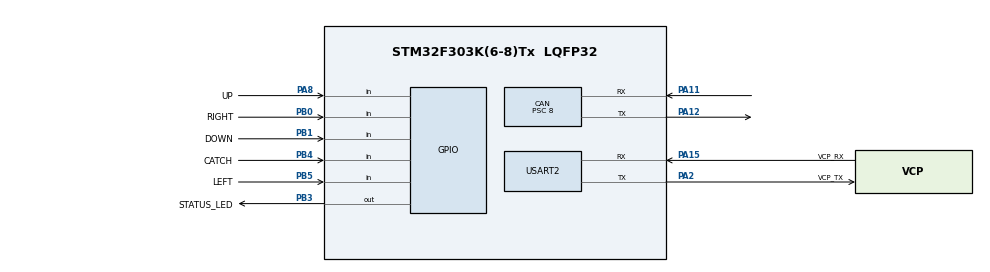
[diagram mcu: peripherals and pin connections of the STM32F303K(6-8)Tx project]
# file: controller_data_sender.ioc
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CAN.BS1=CAN_BS1_7TQ
CAN.BS2=CAN_BS2_2TQ
CAN.CalculateBaudRate=100000
CAN.CalculateTimeBit=10000
CAN.CalculateTimeQuantum=1000.0
CAN.Prescaler=8
CAN.SJW=CAN_SJW_1TQ
Mcu.Family=STM32F3
Mcu.Name=STM32F303K(6-8)Tx
Mcu.Package=LQFP32
NVIC.PriorityGroup=NVIC_PRIORITYGROUP_4
PA11.Mode=CAN_Activate
PA11.Signal=CAN_RX
PA12.Mode=CAN_Activate
PA12.Signal=CAN_TX
PA13.GPIO_Label=SWDIO
PA13.Mode=Serial_Wire
PA13.Signal=SYS_JTMS-SWDIO
PA14.GPIO_Label=SWCLK
PA14.Mode=Serial_Wire
PA14.Signal=SYS_JTCK-SWCLK
PA15.GPIO_Label=VCP_RX
PA15.Mode=Asynchronous
PA15.Signal=USART2_RX
PA2.GPIO_Label=VCP_TX
PA2.Mode=Asynchronous
PA2.Signal=USART2_TX
PA8.GPIO_Label=UP
PA8.GPIO_PuPd=GPIO_PULLUP
PA8.Signal=GPIO_Input
PB0.GPIO_Label=RIGHT
PB0.GPIO_PuPd=GPIO_PULLUP
PB0.Signal=GPIO_Input
PB1.GPIO_Label=DOWN
PB1.GPIO_PuPd=GPIO_PULLUP
PB1.Signal=GPIO_Input
PB3.GPIO_Label=STATUS_LED
PB3.Signal=GPIO_Output
PB4.GPIO_Label=CATCH
PB4.GPIO_PuPd=GPIO_PULLUP
PB4.Signal=GPIO_Input
PB5.GPIO_Label=LEFT
PB5.GPIO_PuPd=GPIO_PULLUP
PB5.Signal=GPIO_Input
PF0\ /\ OSC_IN.GPIO_Label=MCO
PF0\ /\ OSC_IN.Mode=HSE-External-Clock-Source
PF0\ /\ OSC_IN.Signal=RCC_OSC_IN
ProjectManager.HeapSize=0x200
ProjectManager.StackSize=0x400
ProjectManager.TargetToolchain=CMake
RCC.AHBFreq_Value=8000000
RCC.APB1Freq_Value=8000000
RCC.APB2Freq_Value=8000000
RCC.CortexFreq_Value=8000000
RCC.HSE_VALUE=8000000
RCC.HSI_VALUE=8000000
RCC.SYSCLKFreq_VALUE=8000000
RCC.SYSCLKSource=RCC_SYSCLKSOURCE_HSE
USART2.VirtualMode-Asynchronous=VM_ASYNC
board=NUCLEO-F303K8

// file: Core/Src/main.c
/* USER CODE BEGIN Header */
/**
  ******************************************************************************
  * @file           : main.c
  * @brief          : Main program body
  ******************************************************************************
  * @attention
  *
  * Copyright (c) 2026 STMicroelectronics.
  * All rights reserved.
  *
  * This software is licensed under terms that can be found in the LICENSE file
  * in the root directory of this software component.
  * If no LICENSE file comes with this software, it is provided AS-IS.
  *
  ******************************************************************************
  */
/* USER CODE END Header */
#include "main.h"

/* USER CODE BEGIN Includes */
#include "can.h"

/* USER CODE END Includes */

/* USER CODE BEGIN PD */
#define SEND_PERIOD_MS 10

/* USER CODE END PD */

CAN_HandleTypeDef hcan;

UART_HandleTypeDef huart2;

void SystemClock_Config(void);
static void MX_GPIO_Init(void);
static void MX_CAN_Init(void);
static void MX_USART2_UART_Init(void);

int main(void)
{

  /* MCU Configuration--------------------------------------------------------*/

  /* Reset of all peripherals, Initializes the Flash interface and the Systick. */
  HAL_Init();

  /* Configure the system clock */
  SystemClock_Config();

  /* Initialize all configured peripherals */
  MX_GPIO_Init();
  MX_CAN_Init();
  MX_USART2_UART_Init();
  /* USER CODE BEGIN 2 */
  if (HAL_CAN_Start(&hcan) != HAL_OK)
  {
    Error_Handler();
  }

  /* USER CODE END 2 */

  /* Infinite loop */
  while (1)
  {

    /* USER CODE BEGIN 3 */
    // ボタンはプルアップ入力なので押下でLOW
    can_command_data_t com = {.id = CAN_ID_CONTROLLER};
    com.data.con.raw = 0;
    com.data.con.left  = (HAL_GPIO_ReadPin(LEFT_GPIO_Port,  LEFT_Pin)  == GPIO_PIN_RESET);
    com.data.con.right = (HAL_GPIO_ReadPin(RIGHT_GPIO_Port, RIGHT_Pin) == GPIO_PIN_RESET);
    com.data.con.up    = (HAL_GPIO_ReadPin(UP_GPIO_Port,    UP_Pin)    == GPIO_PIN_RESET);
    com.data.con.down  = (HAL_GPIO_ReadPin(DOWN_GPIO_Port,  DOWN_Pin)  == GPIO_PIN_RESET);
    com.data.con.cat   = (HAL_GPIO_ReadPin(CATCH_GPIO_Port, CATCH_Pin) == GPIO_PIN_RESET);

    stm_can_send(&hcan, &com);

    // STATUS_LED: いずれかのボタンが押されている間だけ点灯
    HAL_GPIO_WritePin(STATUS_LED_GPIO_Port, STATUS_LED_Pin,
                      com.data.con.raw ? GPIO_PIN_SET : GPIO_PIN_RESET);
    HAL_Delay(SEND_PERIOD_MS);
  }
  /* USER CODE END 3 */
}

void SystemClock_Config(void)
{
  RCC_OscInitTypeDef RCC_OscInitStruct = {0};
  RCC_ClkInitTypeDef RCC_ClkInitStruct = {0};
  uint32_t sysclk_src = RCC_SYSCLKSOURCE_HSE;

  /** Initializes the RCC Oscillators according to the specified parameters
  * in the RCC_OscInitTypeDef structure.
  */
  RCC_OscInitStruct.OscillatorType = RCC_OSCILLATORTYPE_HSE;
  RCC_OscInitStruct.HSEState = RCC_HSE_BYPASS;
  RCC_OscInitStruct.HSEPredivValue = RCC_HSE_PREDIV_DIV1;
  RCC_OscInitStruct.PLL.PLLState = RCC_PLL_NONE;
  if (HAL_RCC_OscConfig(&RCC_OscInitStruct) != HAL_OK)
  {
    /* HSE(ST-LINKのMCO)が立ち上がらないときはHSIで動かす。システムクロックは同じ8MHz */
    sysclk_src = RCC_SYSCLKSOURCE_HSI;
    RCC_OscInitStruct = (RCC_OscInitTypeDef){0};
    RCC_OscInitStruct.OscillatorType = RCC_OSCILLATORTYPE_HSE|RCC_OSCILLATORTYPE_HSI;
    RCC_OscInitStruct.HSEState = RCC_HSE_OFF;
    RCC_OscInitStruct.HSIState = RCC_HSI_ON;
    RCC_OscInitStruct.HSICalibrationValue = RCC_HSICALIBRATION_DEFAULT;
    RCC_OscInitStruct.PLL.PLLState = RCC_PLL_NONE;
    if (HAL_RCC_OscConfig(&RCC_OscInitStruct) != HAL_OK)
    {
      Error_Handler();
    }
  }

  /** Initializes the CPU, AHB and APB buses clocks
  */
  RCC_ClkInitStruct.ClockType = RCC_CLOCKTYPE_HCLK|RCC_CLOCKTYPE_SYSCLK
                              |RCC_CLOCKTYPE_PCLK1|RCC_CLOCKTYPE_PCLK2;
  RCC_ClkInitStruct.SYSCLKSource = sysclk_src;
  RCC_ClkInitStruct.AHBCLKDivider = RCC_SYSCLK_DIV1;
  RCC_ClkInitStruct.APB1CLKDivider = RCC_HCLK_DIV1;
  RCC_ClkInitStruct.APB2CLKDivider = RCC_HCLK_DIV1;

  if (HAL_RCC_ClockConfig(&RCC_ClkInitStruct, FLASH_LATENCY_0) != HAL_OK)
  {
    Error_Handler();
  }
}

static void MX_CAN_Init(void)
{

  hcan.Instance = CAN;
  hcan.Init.Prescaler = 8;
  hcan.Init.Mode = CAN_MODE_NORMAL;
  hcan.Init.SyncJumpWidth = CAN_SJW_1TQ;
  hcan.Init.TimeSeg1 = CAN_BS1_7TQ;
  hcan.Init.TimeSeg2 = CAN_BS2_2TQ;
  hcan.Init.TimeTriggeredMode = DISABLE;
  hcan.Init.AutoBusOff = DISABLE;
  hcan.Init.AutoWakeUp = DISABLE;
  hcan.Init.AutoRetransmission = DISABLE;
  hcan.Init.ReceiveFifoLocked = DISABLE;
  hcan.Init.TransmitFifoPriority = DISABLE;
  if (HAL_CAN_Init(&hcan) != HAL_OK)
  {
    Error_Handler();
  }

}

static void MX_USART2_UART_Init(void)
{

  huart2.Instance = USART2;
  huart2.Init.BaudRate = 38400;
  huart2.Init.WordLength = UART_WORDLENGTH_8B;
  huart2.Init.StopBits = UART_STOPBITS_1;
  huart2.Init.Parity = UART_PARITY_NONE;
  huart2.Init.Mode = UART_MODE_TX_RX;
  huart2.Init.HwFlowCtl = UART_HWCONTROL_NONE;
  huart2.Init.OverSampling = UART_OVERSAMPLING_16;
  huart2.Init.OneBitSampling = UART_ONE_BIT_SAMPLE_DISABLE;
  huart2.AdvancedInit.AdvFeatureInit = UART_ADVFEATURE_NO_INIT;
  if (HAL_UART_Init(&huart2) != HAL_OK)
  {
    Error_Handler();
  }

}

static void MX_GPIO_Init(void)
{
  GPIO_InitTypeDef GPIO_InitStruct = {0};

  /* GPIO Ports Clock Enable */
  __HAL_RCC_GPIOF_CLK_ENABLE();
  __HAL_RCC_GPIOA_CLK_ENABLE();
  __HAL_RCC_GPIOB_CLK_ENABLE();

  /*Configure GPIO pin Output Level */
  HAL_GPIO_WritePin(STATUS_LED_GPIO_Port, STATUS_LED_Pin, GPIO_PIN_RESET);

  /*Configure GPIO pins : DOWN_Pin RIGHT_Pin LEFT_Pin CATCH_Pin */
  GPIO_InitStruct.Pin = DOWN_Pin|RIGHT_Pin|LEFT_Pin|CATCH_Pin;
  GPIO_InitStruct.Mode = GPIO_MODE_INPUT;
  GPIO_InitStruct.Pull = GPIO_PULLUP;
  HAL_GPIO_Init(GPIOB, &GPIO_InitStruct);

  /*Configure GPIO pin : UP_Pin */
  GPIO_InitStruct.Pin = UP_Pin;
  GPIO_InitStruct.Mode = GPIO_MODE_INPUT;
  GPIO_InitStruct.Pull = GPIO_PULLUP;
  HAL_GPIO_Init(UP_GPIO_Port, &GPIO_InitStruct);

  /*Configure GPIO pin : STATUS_LED_Pin */
  GPIO_InitStruct.Pin = STATUS_LED_Pin;
  GPIO_InitStruct.Mode = GPIO_MODE_OUTPUT_PP;
  GPIO_InitStruct.Pull = GPIO_NOPULL;
  GPIO_InitStruct.Speed = GPIO_SPEED_FREQ_LOW;
  HAL_GPIO_Init(STATUS_LED_GPIO_Port, &GPIO_InitStruct);

}

void Error_Handler(void)
{
  __disable_irq();
  while (1)
  {
  }
}
